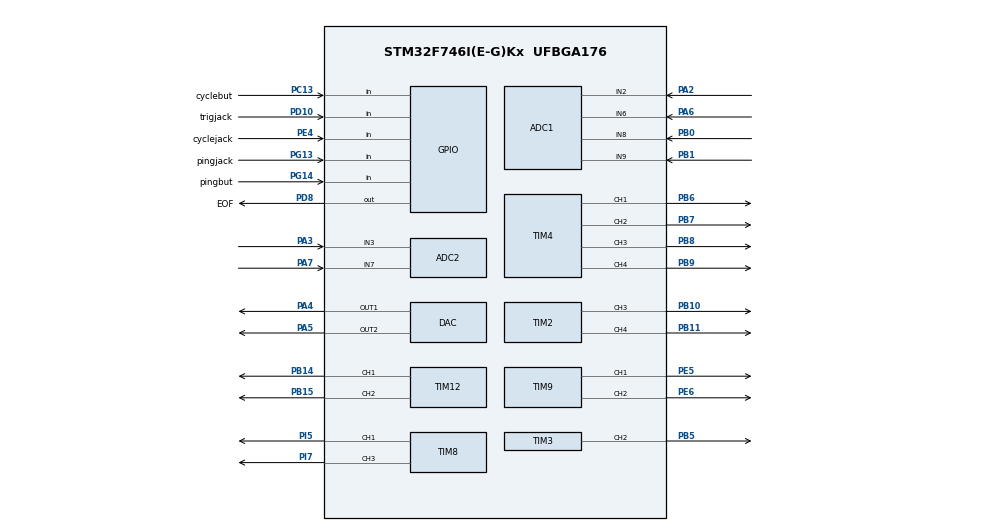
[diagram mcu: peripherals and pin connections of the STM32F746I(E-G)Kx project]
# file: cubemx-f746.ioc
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ADC1.Channel-0\#ChannelRegularConversion=ADC_CHANNEL_2
ADC1.Channel-1\#ChannelRegularConversion=ADC_CHANNEL_6
ADC1.Channel-2\#ChannelRegularConversion=ADC_CHANNEL_8
ADC1.Channel-3\#ChannelRegularConversion=ADC_CHANNEL_9
ADC1.ClockPrescaler=ADC_CLOCK_SYNC_PCLK_DIV4
ADC1.ContinuousConvMode=ENABLE
ADC1.DMAContinuousRequests=ENABLE
ADC1.EOCSelection=ADC_EOC_SEQ_CONV
ADC1.NbrOfConversion=4
ADC1.NbrOfConversionFlag=1
ADC1.Rank-0\#ChannelRegularConversion=1
ADC1.Rank-1\#ChannelRegularConversion=2
ADC1.Rank-2\#ChannelRegularConversion=3
ADC1.Rank-3\#ChannelRegularConversion=4
ADC1.SamplingTime-0\#ChannelRegularConversion=ADC_SAMPLETIME_56CYCLES
ADC1.SamplingTime-1\#ChannelRegularConversion=ADC_SAMPLETIME_56CYCLES
ADC1.SamplingTime-2\#ChannelRegularConversion=ADC_SAMPLETIME_56CYCLES
ADC1.SamplingTime-3\#ChannelRegularConversion=ADC_SAMPLETIME_56CYCLES
ADC1.ScanConvMode=ADC_SCAN_ENABLE
ADC1.master=1
ADC2.Channel-0\#ChannelRegularConversion=ADC_CHANNEL_3
ADC2.Channel-1\#ChannelRegularConversion=ADC_CHANNEL_7
ADC2.ClockPrescaler=ADC_CLOCK_SYNC_PCLK_DIV4
ADC2.DMAContinuousRequests=ENABLE
ADC2.EOCSelection=ADC_EOC_SEQ_CONV
ADC2.NbrOfConversion=2
ADC2.NbrOfConversionFlag=1
ADC2.Rank-0\#ChannelRegularConversion=1
ADC2.Rank-1\#ChannelRegularConversion=2
ADC2.SamplingTime-0\#ChannelRegularConversion=ADC_SAMPLETIME_56CYCLES
ADC2.SamplingTime-1\#ChannelRegularConversion=ADC_SAMPLETIME_56CYCLES
ADC2.ScanConvMode=ADC_SCAN_ENABLE
DAC.DAC_Trigger=DAC_TRIGGER_SOFTWARE
DAC.DAC_Trigger2=DAC_TRIGGER_SOFTWARE
Dma.ADC1.0.Direction=DMA_PERIPH_TO_MEMORY
Dma.ADC1.0.FIFOMode=DMA_FIFOMODE_DISABLE
Dma.ADC1.0.Instance=DMA2_Stream0
Dma.ADC1.0.MemDataAlignment=DMA_MDATAALIGN_HALFWORD
Dma.ADC1.0.MemInc=DMA_MINC_ENABLE
Dma.ADC1.0.Mode=DMA_NORMAL
Dma.ADC1.0.PeriphDataAlignment=DMA_PDATAALIGN_HALFWORD
Dma.ADC1.0.PeriphInc=DMA_PINC_DISABLE
Dma.ADC1.0.Priority=DMA_PRIORITY_HIGH
Dma.ADC2.1.Direction=DMA_PERIPH_TO_MEMORY
Dma.ADC2.1.FIFOMode=DMA_FIFOMODE_DISABLE
Dma.ADC2.1.Instance=DMA2_Stream2
Dma.ADC2.1.MemDataAlignment=DMA_MDATAALIGN_HALFWORD
Dma.ADC2.1.MemInc=DMA_MINC_ENABLE
Dma.ADC2.1.Mode=DMA_NORMAL
Dma.ADC2.1.PeriphDataAlignment=DMA_PDATAALIGN_HALFWORD
Dma.ADC2.1.PeriphInc=DMA_PINC_DISABLE
Dma.ADC2.1.Priority=DMA_PRIORITY_HIGH
Dma.Request0=ADC1
Dma.Request1=ADC2
Mcu.Family=STM32F7
Mcu.Name=STM32F746I(E-G)Kx
Mcu.Package=UFBGA176
NVIC.DMA2_Stream0_IRQn=true\:0\:0\:false\:false\:true\:false\:true
NVIC.DMA2_Stream2_IRQn=true\:0\:0\:false\:false\:true\:false\:true
NVIC.PriorityGroup=NVIC_PRIORITYGROUP_4
PA13.Mode=Trace_Asynchronous_SW
PA13.Signal=SYS_JTMS-SWDIO
PA14.Mode=Trace_Asynchronous_SW
PA14.Signal=SYS_JTCK-SWCLK
PA2.Signal=ADCx_IN2
PA3.Signal=ADCx_IN3
PA4.Signal=COMP_DAC1_group
PA5.Signal=COMP_DAC2_group
PA6.Signal=ADCx_IN6
PA7.Signal=ADCx_IN7
PB0.Signal=ADCx_IN8
PB1.Signal=ADCx_IN9
PB10.Signal=S_TIM2_CH3
PB11.Signal=S_TIM2_CH4
PB14.Signal=S_TIM12_CH1
PB15.Signal=S_TIM12_CH2
PB3.Mode=Trace_Asynchronous_SW
PB3.Signal=SYS_JTDO-SWO
PB5.Signal=S_TIM3_CH2
PB6.Signal=S_TIM4_CH1
PB7.Signal=S_TIM4_CH2
PB8.Signal=S_TIM4_CH3
PB9.Signal=S_TIM4_CH4
PC13.GPIO_Label=cyclebut
PC13.GPIO_PuPd=GPIO_PULLUP
PC13.Signal=GPIO_Input
PD10.GPIO_Label=trigjack
PD10.GPIO_PuPd=GPIO_NOPULL
PD10.Signal=GPIO_Input
PD8.GPIO_Label=EOF
PD8.Signal=GPIO_Output
PE4.GPIO_Label=cyclejack
PE4.Signal=GPIO_Input
PE5.Signal=S_TIM9_CH1
PE6.Signal=S_TIM9_CH2
PG13.GPIO_Label=pingjack
PG13.Signal=GPIO_Input
PG14.GPIO_Label=pingbut
PG14.GPIO_PuPd=GPIO_PULLUP
PG14.Signal=GPIO_Input
PH0/OSC_IN.Mode=HSE-External-Oscillator
PH0/OSC_IN.Signal=RCC_OSC_IN
PH1/OSC_OUT.Mode=HSE-External-Oscillator
PH1/OSC_OUT.Signal=RCC_OSC_OUT
PI5.Signal=S_TIM8_CH1
PI7.Signal=S_TIM8_CH3
ProjectManager.HeapSize=0x200
ProjectManager.StackSize=0x400
ProjectManager.TargetToolchain=Makefile
RCC.AHBFreq_Value=216000000
RCC.APB1CLKDivider=RCC_HCLK_DIV4
RCC.APB1Freq_Value=54000000
RCC.APB1TimFreq_Value=108000000
RCC.APB2CLKDivider=RCC_HCLK_DIV8
RCC.APB2Freq_Value=27000000
RCC.APB2TimFreq_Value=54000000
RCC.CortexFreq_Value=216000000
RCC.HCLKFreq_Value=216000000
RCC.HSE_VALUE=16000000
RCC.HSI_VALUE=16000000
RCC.LSE_VALUE=32768
RCC.PLLM=8
RCC.PLLN=216
RCC.PLLSourceVirtual=RCC_PLLSOURCE_HSE
RCC.SYSCLKFreq_VALUE=216000000
RCC.SYSCLKSource=RCC_SYSCLKSOURCE_PLLCLK
RCC.USBFreq_Value=216000000
RCC.VCOOutputFreq_Value=432000000
SH.ADCx_IN2.0=ADC1_IN2,IN2
SH.ADCx_IN3.0=ADC1_IN3
SH.ADCx_IN3.1=ADC2_IN3,IN3
SH.ADCx_IN6.0=ADC1_IN6,IN6
SH.ADCx_IN7.0=ADC1_IN7
SH.ADCx_IN7.1=ADC2_IN7,IN7
SH.ADCx_IN8.0=ADC1_IN8,IN8
SH.ADCx_IN9.0=ADC1_IN9,IN9
SH.COMP_DAC1_group.0=DAC_OUT1,DAC_OUT1
SH.COMP_DAC2_group.0=DAC_OUT2,DAC_OUT2
SH.S_TIM12_CH1.0=TIM12_CH1,PWM Generation1 CH1
SH.S_TIM12_CH2.0=TIM12_CH2,PWM Generation2 CH2
SH.S_TIM2_CH3.0=TIM2_CH3,PWM Generation3 CH3
SH.S_TIM2_CH4.0=TIM2_CH4,PWM Generation4 CH4
SH.S_TIM3_CH2.0=TIM3_CH2,PWM Generation2 CH2
SH.S_TIM4_CH1.0=TIM4_CH1,PWM Generation1 CH1
SH.S_TIM4_CH2.0=TIM4_CH2,PWM Generation2 CH2
SH.S_TIM4_CH3.0=TIM4_CH3,PWM Generation3 CH3
SH.S_TIM4_CH4.0=TIM4_CH4,PWM Generation4 CH4
SH.S_TIM8_CH1.0=TIM8_CH1,PWM Generation1 CH1
SH.S_TIM8_CH3.0=TIM8_CH3,PWM Generation3 CH3
SH.S_TIM9_CH1.0=TIM9_CH1,Output Compare1 CH1
SH.S_TIM9_CH2.0=TIM9_CH2,Output Compare2 CH2
TIM12.Channel-PWM\ Generation1\ CH1=TIM_CHANNEL_1
TIM12.Channel-PWM\ Generation2\ CH2=TIM_CHANNEL_2
TIM2.Channel-PWM\ Generation3\ CH3=TIM_CHANNEL_3
TIM2.Channel-PWM\ Generation4\ CH4=TIM_CHANNEL_4
TIM3.Channel-PWM\ Generation2\ CH2=TIM_CHANNEL_2
TIM4.Channel-PWM\ Generation1\ CH1=TIM_CHANNEL_1
TIM4.Channel-PWM\ Generation2\ CH2=TIM_CHANNEL_2
TIM4.Channel-PWM\ Generation3\ CH3=TIM_CHANNEL_3
TIM4.Channel-PWM\ Generation4\ CH4=TIM_CHANNEL_4
TIM8.Channel-PWM\ Generation1\ CH1=TIM_CHANNEL_1
TIM8.Channel-PWM\ Generation3\ CH3=TIM_CHANNEL_3
TIM9.Channel-Output\ Compare1\ CH1=TIM_CHANNEL_1
TIM9.Channel-Output\ Compare2\ CH2=TIM_CHANNEL_2
board=custom

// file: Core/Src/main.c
/* USER CODE BEGIN Header */
/**
  ******************************************************************************
  * @file           : main.c
  * @brief          : Main program body
  ******************************************************************************
  * @attention
  *
  * Copyright (c) 2022 STMicroelectronics.
  * All rights reserved.
  *
  * This software is licensed under terms that can be found in the LICENSE file
  * in the root directory of this software component.
  * If no LICENSE file comes with this software, it is provided AS-IS.
  *
  ******************************************************************************
  */
/* USER CODE END Header */
#include "main.h"
#include "adc.h"
#include "dac.h"
#include "dma.h"
#include "tim.h"
#include "gpio.h"

void SystemClock_Config(void);

int main(void)
{

  /* MCU Configuration--------------------------------------------------------*/

  /* Reset of all peripherals, Initializes the Flash interface and the Systick. */
  HAL_Init();

  /* Configure the system clock */
  SystemClock_Config();

  /* Initialize all configured peripherals */
  MX_GPIO_Init();
  MX_DMA_Init();
  MX_ADC1_Init();
  MX_DAC_Init();
  MX_TIM2_Init();
  MX_TIM3_Init();
  MX_TIM4_Init();
  MX_TIM8_Init();
  MX_TIM9_Init();
  MX_TIM12_Init();
  MX_ADC2_Init();

  /* Infinite loop */
	while (1) {

	}
}

void SystemClock_Config(void)
{
  RCC_OscInitTypeDef RCC_OscInitStruct = {0};
  RCC_ClkInitTypeDef RCC_ClkInitStruct = {0};

  /** Configure the main internal regulator output voltage
  */
  __HAL_RCC_PWR_CLK_ENABLE();
  __HAL_PWR_VOLTAGESCALING_CONFIG(PWR_REGULATOR_VOLTAGE_SCALE1);
  /** Initializes the RCC Oscillators according to the specified parameters
  * in the RCC_OscInitTypeDef structure.
  */
  RCC_OscInitStruct.OscillatorType = RCC_OSCILLATORTYPE_HSE;
  RCC_OscInitStruct.HSEState = RCC_HSE_ON;
  RCC_OscInitStruct.PLL.PLLState = RCC_PLL_ON;
  RCC_OscInitStruct.PLL.PLLSource = RCC_PLLSOURCE_HSE;
  RCC_OscInitStruct.PLL.PLLM = 8;
  RCC_OscInitStruct.PLL.PLLN = 216;
  RCC_OscInitStruct.PLL.PLLP = RCC_PLLP_DIV2;
  RCC_OscInitStruct.PLL.PLLQ = 2;
  if (HAL_RCC_OscConfig(&RCC_OscInitStruct) != HAL_OK)
  {
    Error_Handler();
  }
  /** Activate the Over-Drive mode
  */
  if (HAL_PWREx_EnableOverDrive() != HAL_OK)
  {
    Error_Handler();
  }
  /** Initializes the CPU, AHB and APB buses clocks
  */
  RCC_ClkInitStruct.ClockType = RCC_CLOCKTYPE_HCLK|RCC_CLOCKTYPE_SYSCLK
                              |RCC_CLOCKTYPE_PCLK1|RCC_CLOCKTYPE_PCLK2;
  RCC_ClkInitStruct.SYSCLKSource = RCC_SYSCLKSOURCE_PLLCLK;
  RCC_ClkInitStruct.AHBCLKDivider = RCC_SYSCLK_DIV1;
  RCC_ClkInitStruct.APB1CLKDivider = RCC_HCLK_DIV4;
  RCC_ClkInitStruct.APB2CLKDivider = RCC_HCLK_DIV2;

  if (HAL_RCC_ClockConfig(&RCC_ClkInitStruct, FLASH_LATENCY_7) != HAL_OK)
  {
    Error_Handler();
  }
}

void Error_Handler(void)
{
	__disable_irq();
	while (1) {
	}
}
